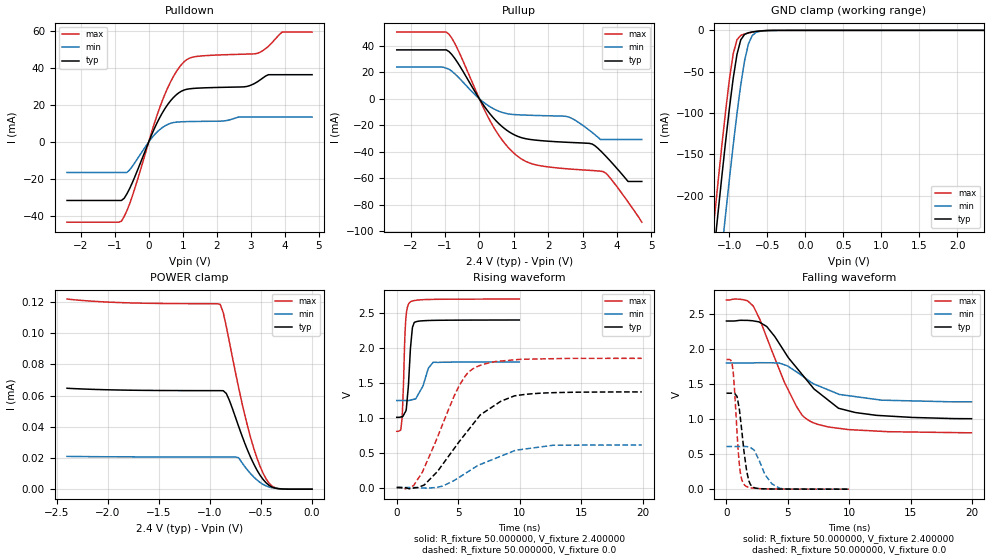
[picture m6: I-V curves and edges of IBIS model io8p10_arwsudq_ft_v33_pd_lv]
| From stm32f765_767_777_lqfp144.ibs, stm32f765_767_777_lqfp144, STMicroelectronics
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|   Model io8p10_arwsudq_ft_v33_pd_lv
[Model]  io8p10_arwsudq_ft_v33_pd_lv
Model_type I/O
Polarity   Non-Inverting
Enable   Active-Low
Vinl =   0.720000V
Vinh =   1.680000V
Vmeas =  1.200000V
Cref =   40.000000pF
Rref =   100.000000M
Vref =   0.0V
C_comp   2.828400pF   2.771400pF   2.910300pF
[Temperature Range]   25.000000   0.125000k   -40.000000
[Pullup Reference]   2.400000V   1.800000V   2.700000V
[Pulldown Reference]   0.0V   0.0V   0.0V
[POWER Clamp Reference]   2.400000V   1.800000V   2.700000V
[GND Clamp Reference]   0.0V   0.0V   0.0V
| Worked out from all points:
|   slope of the pulldown table from 0 to 0.36 V, typ, clamps not added: 25 ohm
|   slope of the pullup table from 0 to 0.36 V, typ, clamps not added: 27.7 ohm
|   GND clamp passes 1 mA (typ) near -0.62 V on its own axis
|   rising waveform, R_fixture 50.000000, V_fixture 2.400000: 20-80 % time 323ps typ, 715ps min, 223ps max; typ from 1 V to 2.4 V
|   rising waveform, R_fixture 50.000000, V_fixture 0.0: 20-80 % time 3.77ns typ, 4.14ns min, 2.7ns max; typ from 0 V to 1.37 V
|   falling waveform, R_fixture 50.000000, V_fixture 2.400000: 20-80 % time 4.04ns typ, 3.55ns min, 2.76ns max; typ from 2.4 V to 1 V
|   falling waveform, R_fixture 50.000000, V_fixture 0.0: 20-80 % time 552ps typ, 1.05ns min, 408ps max; typ from 1.37 V to 0 V
[Pulldown]
|Voltage   I(typ)   I(min)   I(max)
-2.4V     -31.66mA   -16.51mA   -43.43mA
-800mV    -31.66mA   -16.51mA   -42.86mA
-480mV    -21.98mA   -13.17mA   -29.2mA
80mV      3.63mA     1.966mA    5.014mA
480mV     18.15mA    8.738mA    26.02mA
800mV     25.38mA    10.72mA    37.77mA
1.12V     28.53mA    11.02mA    44.6mA
2.8V      29.84mA    13.48mA    47.53mA
3.2V      32.65mA    13.48mA    48.04mA
3.52V     36.42mA    13.48mA    51.83mA
3.92V     36.42mA    13.48mA    59.48mA
4.8V      36.42mA    13.48mA    59.48mA
[Pullup]
|Voltage   I(typ)   I(min)   I(max)
-2.4V     36.9mA     24.04mA    50.34mA
-960mV    36.9mA     23.05mA    50.34mA
-640mV    27.65mA    17.04mA    37.98mA
320mV     -11.75mA   -6.207mA   -17.08mA
640mV     -20.52mA   -10.1mA    -30.35mA
960mV     -26.47mA   -11.82mA   -40.02mA
1.52V     -30.88mA   -12.51mA   -49.05mA
2.56V     -32.88mA   -13.49mA   -52.9mA
3.28V     -34.2mA    -25.51mA   -54.18mA
3.6V      -41.34mA   -30.76mA   -55mA
4.32V     -62.43mA   -30.76mA   -77.88mA
4.72V     -62.43mA   -30.76mA   -93.2mA
[GND_clamp]
|Voltage   I(typ)   I(min)   I(max)
-2.4V     -1.428A    -1.51A     -1.4A
-1.2V     -266.4mA   -356.3mA   -229.4mA
-1.15V    -221.3mA   -311mA     -184.1mA
-1.1V     -177.3mA   -266.4mA   -140mA
-1.05V    -134.8mA   -222.7mA   -97.98mA
-950mV    -58.22mA   -139.2mA   -28.55mA
-900mV    -29.04mA   -100.6mA   -11.28mA
-850mV    -11.42mA   -65.77mA   -6.081mA
-750mV    -2.864mA   -16.63mA   -3.193mA
-700mV    -1.925mA   -6.327mA   -2.195mA
-600mV    -761.3uA   -1.176mA   -751.9uA
2.35V     58.09uA    37.92uA    67.25uA
[POWER_clamp]
|Voltage   I(typ)   I(min)   I(max)
-2.4V     64.71uA    21.03uA    121.9uA
-1.86V    63.55uA    20.74uA    119.6uA
-900mV    63.18uA    20.63uA    118.5uA
-870mV    63.14uA    20.63uA    113.2uA
-840mV    61.36uA    20.62uA    104.3uA
-720mV    40.37uA    20.18uA    65.28uA
-630mV    24.69uA    12.08uA    39.85uA
-540mV    12.26uA    5.907uA    20uA
-480mV    6.236uA    3.061uA    10.23uA
-420mV    2.4uA      1.365uA    3.726uA
-360mV    667.9nA    564nA      839.6nA
0V        0A         0A         0A
[Ramp]
| variable   typ   min   max
dV/dt_r  0.82152/3.77198n   0.36526/4.13997n   1.11090/2.69800n
dV/dt_f  0.83268/4.02902n   0.33432/3.60770n   1.13614/2.75462n
R_load = 50.000000
[Rising Waveform]
R_fixture= 50.000000
V_fixture= 2.400000
V_fixture_min= 1.800000
V_fixture_max= 2.700000
|time   V(typ)   V(min)   V(max)
0s        1.005V     1.245V     804.5mV
320.3ps   1.01V      1.245V     823mV
440.4ps   1.015V     1.245V     996mV
720.7ps   1.09V      1.245V     2.367V
940.9ps   1.443V     1.245V     2.62V
1.041ns   1.754V     1.248V     2.648V
1.281ns   2.297V     1.259V     2.671V
1.481ns   2.368V     1.267V     2.679V
2.963ns   2.393V     1.793V     2.694V
9.97ns    2.399V     1.799V     2.699V
[Rising Waveform]
R_fixture= 50.000000
V_fixture= 0.0
V_fixture_min= 0.0
V_fixture_max= 0.0
|time   V(typ)   V(min)   V(max)
0s        76.6uV     35.13uV    232.4uV
1.361ns   -8.148mV   -490.5uV   26.83mV
2.082ns   25.49mV    -6.756mV   218.5mV
4.765ns   580.6mV    110.6mV    1.346V
5.566ns   765mV      200.1mV    1.594V
6.326ns   934.7mV    285.2mV    1.713V
8.448ns   1.233V     447.3mV    1.811V
9.57ns    1.312V     527.1mV    1.828V
12.77ns   1.358V     606mV      1.845V
19.94ns   1.369V     608.5mV    1.85V
[Falling Waveform]
R_fixture= 50.000000
V_fixture= 2.400000
V_fixture_min= 1.800000
V_fixture_max= 2.700000
|time   V(typ)   V(min)   V(max)
0s        2.399V     1.799V     2.699V
1.682ns   2.408V     1.799V     2.689V
2.202ns   2.4V       1.801V     2.607V
3.283ns   2.319V     1.803V     2.161V
4.725ns   1.961V     1.774V     1.523V
6.166ns   1.634V     1.616V     1.053V
6.847ns   1.489V     1.53V      965.5mV
9.129ns   1.154V     1.356V     868.2mV
10.49ns   1.093V     1.32V      844.7mV
19.94ns   1.005V     1.245V     804.5mV
[Falling Waveform]
R_fixture= 50.000000
V_fixture= 0.0
V_fixture_min= 0.0
V_fixture_max= 0.0
|time   V(typ)   V(min)   V(max)
0s        1.369V     608.5mV    1.85V
460.5ps   1.37V      608.4mV    1.789V
660.7ps   1.365V     608.3mV    1.411V
1.041ns   1.152V     608mV      368mV
1.481ns   467.9mV    609.1mV    57.69mV
1.822ns   120mV      605mV      26.12mV
2.282ns   20.12mV    548.2mV    13.09mV
3.143ns   4.546mV    206.3mV    4.902mV
4.364ns   1.707mV    10.24mV    1.639mV
9.97ns    76.6uV     35.13uV    232.4uV
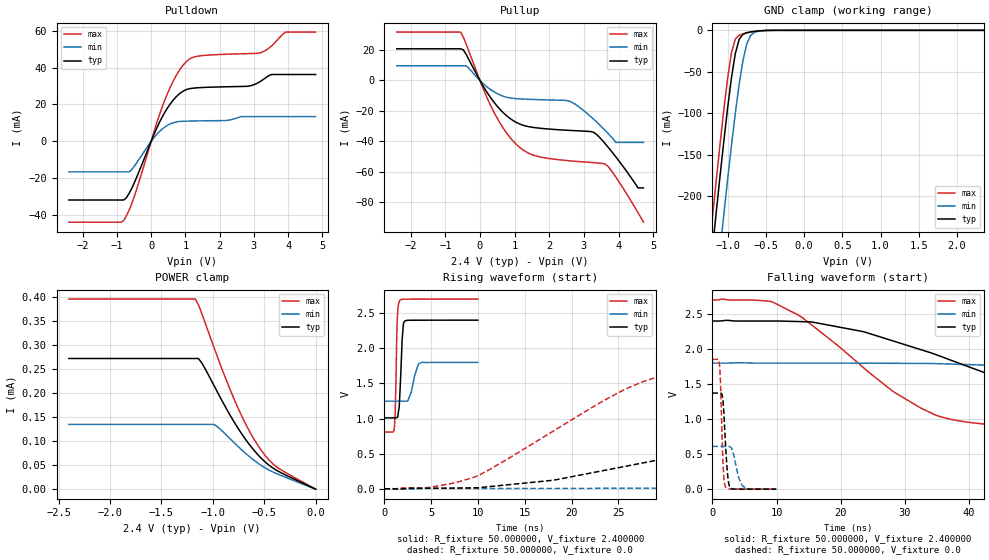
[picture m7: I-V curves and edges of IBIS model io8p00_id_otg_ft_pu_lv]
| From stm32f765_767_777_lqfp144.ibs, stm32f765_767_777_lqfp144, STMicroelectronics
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|   Model io8p00_id_otg_ft_pu_lv
[Model]  io8p00_id_otg_ft_pu_lv
Model_type I/O
Polarity   Non-Inverting
Enable   Active-Low
Vinl =   0.720000V
Vinh =   1.680000V
Vmeas =  1.200000V
Cref =   50.000000pF
Rref =   100.000000M
Vref =   0.0V
C_comp   2.229800pF   2.169700pF   2.325100pF
[Temperature Range]   25.000000   0.125000k   -40.000000
[Pullup Reference]   2.400000V   1.800000V   2.700000V
[Pulldown Reference]   0.0V   0.0V   0.0V
[POWER Clamp Reference]   2.400000V   1.800000V   2.700000V
[GND Clamp Reference]   0.0V   0.0V   0.0V
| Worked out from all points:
|   slope of the pulldown table from 0 to 0.36 V, typ, clamps not added: 25 ohm
|   slope of the pullup table from 0 to 0.36 V, typ, clamps not added: 27.7 ohm
|   GND clamp passes 1 mA (typ) near -0.62 V on its own axis
|   rising waveform, R_fixture 50.000000, V_fixture 2.400000: 20-80 % time 270ps typ, 604ps min, 181ps max; typ from 1.01 V to 2.4 V
|   rising waveform, R_fixture 50.000000, V_fixture 0.0: 20-80 % time 32.6ns typ, 82.1ns min, 14.4ns max; typ from 0.004 V to 1.37 V
|   falling waveform, R_fixture 50.000000, V_fixture 2.400000: 20-80 % time 29.2ns typ, 75.2ns min, 16.2ns max; typ from 2.4 V to 1.01 V
|   falling waveform, R_fixture 50.000000, V_fixture 0.0: 20-80 % time 522ps typ, 976ps min, 385ps max; typ from 1.37 V to 0.004 V
[Pulldown]
|Voltage   I(typ)   I(min)   I(max)
-2.4V     -31.73mA   -16.51mA   -43.74mA
-800mV    -31.73mA   -16.51mA   -42.87mA
-480mV    -21.97mA   -13.17mA   -29.21mA
80mV      3.63mA     1.966mA    5.014mA
480mV     18.15mA    8.737mA    26.02mA
800mV     25.37mA    10.72mA    37.77mA
1.12V     28.53mA    11.02mA    44.6mA
2.8V      29.84mA    13.45mA    47.53mA
3.2V      32.6mA     13.45mA    48.03mA
3.52V     36.23mA    13.45mA    51.75mA
3.92V     36.23mA    13.45mA    59.19mA
4.8V      36.23mA    13.45mA    59.19mA
[Pullup]
|Voltage   I(typ)   I(min)   I(max)
-2.4V     20.88mA    9.658mA    31.88mA
-560mV    20.88mA    9.658mA    31.88mA
-400mV    17.27mA    9.658mA    24.06mA
320mV     -11.75mA   -6.206mA   -17.08mA
960mV     -26.46mA   -11.81mA   -40.01mA
1.52V     -30.88mA   -12.51mA   -49.04mA
2.56V     -32.87mA   -13.48mA   -52.89mA
3.28V     -34.17mA   -25.51mA   -54.16mA
3.6V      -41.29mA   -32.61mA   -54.95mA
3.92V     -50.31mA   -40.8mA    -63.6mA
4.56V     -70.8mA    -40.8mA    -87.05mA
4.72V     -70.8mA    -40.8mA    -93.4mA
[GND_clamp]
|Voltage   I(typ)   I(min)   I(max)
-2.4V     -1.424A    -1.508A    -1.393A
-1.25V    -311.2mA   -401.9mA   -273.3mA
-1.2V     -265.4mA   -356.1mA   -227.2mA
-1.15V    -220.4mA   -310.8mA   -181.9mA
-1.1V     -176.3mA   -266.2mA   -137.9mA
-1.05V    -133.8mA   -222.5mA   -95.88mA
-950mV    -57.31mA   -138.9mA   -26.99mA
-900mV    -28.28mA   -100.4mA   -10.61mA
-850mV    -11.02mA   -65.55mA   -5.978mA
-750mV    -2.847mA   -16.51mA   -3.192mA
-600mV    -755.4uA   -1.17mA    -743.6uA
2.35V     0A         0A         0A
[POWER_clamp]
|Voltage   I(typ)   I(min)   I(max)
-2.4V     272.5uA    135uA      396.5uA
-1.17V    272.5uA    135uA      396.5uA
-1.14V    272.5uA    135uA      384.7uA
-1.11V    264.2uA    135uA      368uA
-990mV    216.8uA    135uA      296.5uA
-870mV    168.8uA    113.3uA    228.2uA
-750mV    125.6uA    88.19uA    167.1uA
-660mV    97.6uA     70.82uA    127.5uA
-570mV    73.91uA    55.62uA    94.12uA
-480mV    54.73uA    43.14uA    67.37uA
-390mV    40.65uA    33.48uA    48.23uA
0V        0A         0A         0A
[Ramp]
| variable   typ   min   max
dV/dt_r  0.82171/32.50848n   0.36348/85.19252n   1.11014/14.36435n
dV/dt_f  0.83394/29.20303n   0.32604/80.16786n   1.13448/16.16075n
R_load = 50.000000
[Rising Waveform]
R_fixture= 50.000000
V_fixture= 2.400000
V_fixture_min= 1.800000
V_fixture_max= 2.700000
|time   V(typ)   V(min)   V(max)
0s        1.011V     1.249V     809.2mV
1.041ns   1.011V     1.249V     835.9mV
1.141ns   1.011V     1.249V     1.047V
1.381ns   1.02V      1.249V     2.448V
1.642ns   1.342V     1.249V     2.681V
1.902ns   2.144V     1.249V     2.696V
2.162ns   2.386V     1.247V     2.698V
2.843ns   2.399V     1.369V     2.699V
3.644ns   2.4V       1.777V     2.7V
9.97ns    2.4V       1.8V       2.7V
[Rising Waveform]
R_fixture= 50.000000
V_fixture= 0.0
V_fixture_min= 0.0
V_fixture_max= 0.0
|time   V(typ)   V(min)   V(max)
0s        3.576mV    3.22mV     3.769mV
4.505ns   11.69mV    7.453mV    18.25mV
9.51ns    16.98mV    7.399mV    164.6mV
26.53ns   343.2mV    11.42mV    1.466V
31.53ns   474.1mV    16.21mV    1.659V
37.04ns   637.8mV    31.84mV    1.748V
56.56ns   1.1V       87.25mV    1.83V
78.58ns   1.316V     193.6mV    1.849V
147.6ns   1.371V     494.9mV    1.854V
249.2ns   1.373V     613.6mV    1.854V
[Falling Waveform]
R_fixture= 50.000000
V_fixture= 2.400000
V_fixture_min= 1.800000
V_fixture_max= 2.700000
|time   V(typ)   V(min)   V(max)
0s        2.4V       1.8V       2.7V
9.51ns    2.4V       1.8V       2.665V
14.01ns   2.391V     1.8V       2.449V
23.52ns   2.249V     1.799V     1.737V
32.53ns   1.991V     1.796V     1.157V
44.04ns   1.614V     1.767V     915.1mV
60.56ns   1.239V     1.708V     851.8mV
86.09ns   1.081V     1.566V     822.9mV
180.7ns   1.015V     1.277V     809.1mV
249.2ns   1.011V     1.249V     809.2mV
[Falling Waveform]
R_fixture= 50.000000
V_fixture= 0.0
V_fixture_min= 0.0
V_fixture_max= 0.0
|time   V(typ)   V(min)   V(max)
0s        1.373V     613.6mV    1.854V
1.061ns   1.373V     613.6mV    1.821V
1.241ns   1.373V     613.6mV    1.573V
1.682ns   1.236V     613.3mV    323.8mV
1.842ns   1.006V     613mV      115.8mV
2.042ns   657.4mV    612.9mV    36.8mV
2.482ns   121.7mV    615.2mV    7.795mV
2.843ns   20.38mV    598.6mV    5.548mV
4.645ns   3.639mV    55.96mV    4.984mV
9.97ns    3.576mV    3.22mV     3.769mV
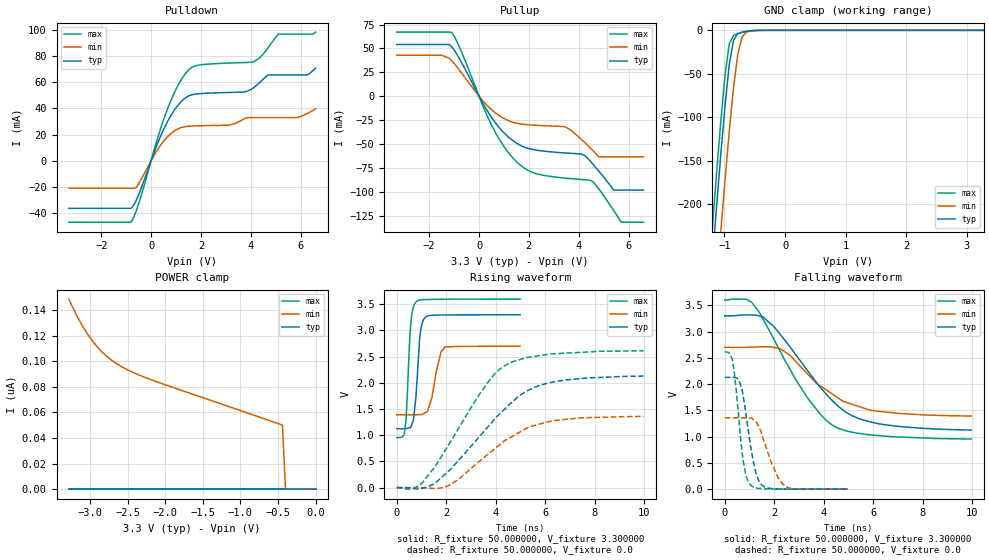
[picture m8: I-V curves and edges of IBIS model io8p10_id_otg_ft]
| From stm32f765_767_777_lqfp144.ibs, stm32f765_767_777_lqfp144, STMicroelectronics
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|   Model io8p10_id_otg_ft
[Model]  io8p10_id_otg_ft
Model_type I/O
Polarity   Non-Inverting
Enable   Active-Low
Vinl =   0.990000V
Vinh =   2.310000V
Vmeas =  1.650000V
Cref =   40.000000pF
Rref =   100.000000M
Vref =   0.0V
C_comp   2.283100pF   2.214500pF   2.357400pF
[Temperature Range]   25.000000   0.125000k   -40.000000
[Pullup Reference]   3.300000V   2.700000V   3.600000V
[Pulldown Reference]   0.0V   0.0V   0.0V
[POWER Clamp Reference]   3.300000V   2.700000V   3.600000V
[GND Clamp Reference]   0.0V   0.0V   0.0V
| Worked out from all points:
|   slope of the pulldown table from 0 to 0.495 V, typ, clamps not added: 20.9 ohm
|   slope of the pullup table from 0 to 0.495 V, typ, clamps not added: 22.6 ohm
|   GND clamp passes 1 mA (typ) near -0.62 V on its own axis
|   rising waveform, R_fixture 50.000000, V_fixture 3.300000: 20-80 % time 194ps typ, 334ps min, 165ps max; typ from 1.12 V to 3.3 V
|   rising waveform, R_fixture 50.000000, V_fixture 0.0: 20-80 % time 2.51ns typ, 2.3ns min, 2.11ns max; typ from 0 V to 2.13 V
|   falling waveform, R_fixture 50.000000, V_fixture 3.300000: 20-80 % time 2.25ns typ, 2.05ns min, 2.02ns max; typ from 3.3 V to 1.12 V
|   falling waveform, R_fixture 50.000000, V_fixture 0.0: 20-80 % time 434ps typ, 634ps min, 340ps max; typ from 2.13 V to 0 V
[Pulldown]
|Voltage   I(typ)   I(min)   I(max)
-3.3V     -36.46mA   -21.09mA   -47.09mA
-800mV    -36.46mA   -21.09mA   -47.09mA
-600mV    -30.5mA    -20.54mA   -38.68mA
700mV     31.4mA     19.11mA    41.71mA
1.2V      45.15mA    25.37mA    61.75mA
1.6V      50.35mA    26.5mA     71.06mA
3.1V      52.28mA    27.26mA    74.76mA
4.1V      55.71mA    33mA       75.81mA
4.7V      65.72mA    33mA       86.7mA
5.1V      65.72mA    33mA       96.91mA
6.3V      65.88mA    36.51mA    96.91mA
6.6V      70.94mA    39.72mA    98.51mA
[Pullup]
|Voltage   I(typ)   I(min)   I(max)
-3.3V     54.23mA    42.91mA    67.19mA
-1.1V     51.99mA    37.29mA    66.9mA
500mV     -22.07mA   -14mA      -30.03mA
1.5V      -49.1mA    -28.3mA    -68.56mA
2.2V      -56.05mA   -30.32mA   -80.35mA
3.5V      -59.53mA   -32.65mA   -85.92mA
4.2V      -61.43mA   -47.49mA   -87.46mA
4.5V      -69.06mA   -55.12mA   -88.38mA
4.8V      -78.22mA   -63.5mA    -96.84mA
5.4V      -98.3mA    -63.5mA    -119.6mA
5.7V      -98.3mA    -63.5mA    -132mA
6.6V      -98.3mA    -63.5mA    -132mA
[GND_clamp]
|Voltage   I(typ)   I(min)   I(max)
-3.3V     -2.318A    -2.397A    -2.291A
-1.2V     -265.5mA   -356.1mA   -227.2mA
-1.13V    -202.7mA   -292.9mA   -164.1mA
-1.06V    -142.2mA   -231.2mA   -104.1mA
-990mV    -85.98mA   -171.6mA   -50.73mA
-920mV    -38.81mA   -115.5mA   -15.3mA
-850mV    -11.1mA    -65.61mA   -6.021mA
-780mV    -3.796mA   -27.43mA   -3.892mA
-710mV    -2.096mA   -7.699mA   -2.393mA
-640mV    -1.154mA   -2.125mA   -1.227mA
-570mV    -528.1uA   -803.6uA   -480.7uA
3.28V     0A         0A         0A
[POWER_clamp]
|Voltage   I(typ)   I(min)   I(max)
-3.28V    0A         148.5nA    0A
-3.2V     0A         138.6nA    0A
-3.12V    0A         129.7nA    0A
-3.04V    0A         122nA      0A
-2.96V    0A         115.3nA    0A
-2.8V     0A         105.1nA    0A
-2.6V     0A         96.44nA    0A
-2.4V     0A         90.52nA    0A
-2.16V    0A         84.97nA    0A
-440mV    0A         50.04nA    0A
-400mV    0A         0A         0A
0V        0A         0A         0A
[Ramp]
| variable   typ   min   max
dV/dt_r  1.26744/2.50778n   0.81174/2.29895n   1.56534/2.11297n
dV/dt_f  1.28322/2.23941n   0.77796/2.04214n   1.57513/2.02611n
R_load = 50.000000
[Rising Waveform]
R_fixture= 50.000000
V_fixture= 3.300000
V_fixture_min= 2.700000
V_fixture_max= 3.600000
|time   V(typ)   V(min)   V(max)
0s        1.124V     1.392V     954.3mV
300.3ps   1.126V     1.392V     1.016V
370.4ps   1.128V     1.392V     1.28V
550.6ps   1.148V     1.392V     3.026V
760.8ps   1.673V     1.391V     3.534V
940.9ps   2.919V     1.394V     3.582V
1.171ns   3.258V     1.435V     3.59V
1.782ns   3.295V     2.582V     3.595V
1.962ns   3.295V     2.688V     3.596V
4.985ns   3.3V       2.7V       3.599V
[Rising Waveform]
R_fixture= 50.000000
V_fixture= 0.0
V_fixture_min= 0.0
V_fixture_max= 0.0
|time   V(typ)   V(min)   V(max)
0s        344.5uV    197.2uV    679.4uV
460.5ps   -2.483mV   133.5uV    -29.04mV
1.041ns   -10.15mV   -1.938mV   97.36mV
1.542ns   81.99mV    -17.46mV   399.1mV
2.162ns   344.4mV    55.54mV    869.4mV
3.744ns   1.193V     660.3mV    2.049V
4.444ns   1.538V     920mV      2.349V
5.285ns   1.851V     1.144V     2.484V
6.166ns   2.001V     1.263V     2.547V
9.97ns    2.129V     1.359V     2.612V
[Falling Waveform]
R_fixture= 50.000000
V_fixture= 3.300000
V_fixture_min= 2.700000
V_fixture_max= 3.600000
|time   V(typ)   V(min)   V(max)
0s        3.3V       2.7V       3.599V
880.9ps   3.316V     2.7V       3.613V
1.101ns   3.315V     2.702V     3.552V
1.542ns   3.279V     2.711V     3.242V
2.242ns   2.946V     2.674V     2.623V
3.383ns   2.234V     2.175V     1.713V
4.404ns   1.658V     1.794V     1.204V
5.125ns   1.403V     1.619V     1.086V
6.206ns   1.247V     1.484V     1.021V
9.97ns    1.124V     1.392V     954.3mV
[Falling Waveform]
R_fixture= 50.000000
V_fixture= 0.0
V_fixture_min= 0.0
V_fixture_max= 0.0
|time   V(typ)   V(min)   V(max)
0s        2.129V     1.359V     2.612V
300.3ps   2.13V      1.359V     2.474V
450.5ps   2.119V     1.358V     1.956V
620.6ps   2.015V     1.358V     1.086V
840.8ps   1.49V      1.36V      300.4mV
1.041ns   832.6mV    1.352V     82.68mV
1.451ns   104.5mV    1.114V     11.66mV
1.882ns   12.98mV    512mV      4.085mV
2.432ns   2.89mV     62.44mV    2.063mV
4.985ns   344.5uV    197.2uV    679.4uV
